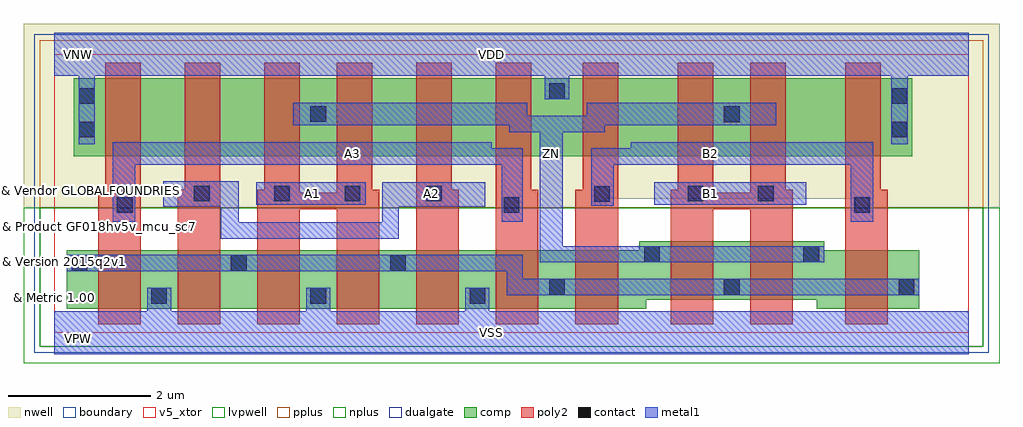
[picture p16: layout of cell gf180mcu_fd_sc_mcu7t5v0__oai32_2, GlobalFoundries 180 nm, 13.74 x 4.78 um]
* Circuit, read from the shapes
.subckt gf180mcu_fd_sc_mcu7t5v0__oai32_2 A1 A2 A3 B1 B2 VDD VNW VSS ZN
XM1 VSS A3 n1 VSUBS nfet_05v0 w=0.82u l=0.6u m=2
XM2 n1 A2 VSS VSUBS nfet_05v0 w=0.82u l=0.6u m=2
XM3 VSS A1 n1 VSUBS nfet_05v0 w=0.82u l=0.6u m=2
XM4 ZN B2 n1 VSUBS nfet_05v0 w=0.82u l=0.6u m=2
XM5 n1 B1 ZN VSUBS nfet_05v0 w=0.82u l=0.6u m=2
XM6 n2 A3 VDD VNW pfet_05v0 w=1.095u l=0.5u
XM7 n3 A2 n2 VNW pfet_05v0 w=1.095u l=0.5u
XM8 ZN A1 n3 VNW pfet_05v0 w=1.095u l=0.5u
XM9 n4 A1 ZN VNW pfet_05v0 w=1.095u l=0.5u
XM10 n5 A2 n4 VNW pfet_05v0 w=1.095u l=0.5u
XM11 VDD A3 n5 VNW pfet_05v0 w=1.095u l=0.5u
XM12 n6 B2 VDD VNW pfet_05v0 w=1.095u l=0.5u
XM13 ZN B1 n6 VNW pfet_05v0 w=1.095u l=0.5u
XM14 n7 B1 ZN VNW pfet_05v0 w=1.095u l=0.5u
XM15 VDD B2 n7 VNW pfet_05v0 w=1.095u l=0.5u
.ends

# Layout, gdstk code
import gdstk
lib = gdstk.Library(unit=1e-6, precision=1e-09)
def R(c, l, rs):  # rectangles x0, y0, x1, y1
    for r in rs: c.add(gdstk.rectangle(r[:2], r[2:], *l))
def A(c, l, x, y, w, h, nx, ny, dx, dy):  # array of equal rectangles
    R(c, l, [(x+i*dx, y+j*dy, x+i*dx+w, y+j*dy+h) for i in range(nx) for j in range(ny)])
def P(c, l, *ps):  # polygons
    for p in ps: c.add(gdstk.Polygon(p, *l))
boundary = (0, 0)
nwell = (21, 0)
comp = (22, 0)
poly2 = (30, 0)
pplus = (31, 0)
nplus = (32, 0)
contact = (33, 0)
metal1 = (34, 0)
dualgate = (55, 0)
v5_xtor = (112, 1)
lvpwell = (204, 0)

gf180mcu_fd_sc_mcu7t5v0_ = lib.new_cell('gf180mcu_fd_sc_mcu7t5v0__oai32_2')
R(gf180mcu_fd_sc_mcu7t5v0_, boundary, [(0,0,12.88,3.92)])
P(gf180mcu_fd_sc_mcu7t5v0_, nwell, [(-0.43,1.76),(-0.43,4.35),(13.31,4.35),(13.31,1.76),(11.28,1.76),(11.28,1.885),(7.77,1.885),(7.77,1.76)])
R(gf180mcu_fd_sc_mcu7t5v0_, comp, [(0.28,2.485,12.08,3.58)])
P(gf180mcu_fd_sc_mcu7t5v0_, comp, [(0.18,0.34),(0.18,1.16),(8.24,1.16),(8.24,1.285),(10.84,1.285),(10.84,1.16),(12.18,1.16),(12.18,0.34),(10.74,0.34),(10.74,0.465),(8.34,0.465),(8.34,0.34)])
P(gf180mcu_fd_sc_mcu7t5v0_, poly2, [(0.62,0.12),(0.62,2.01),(0.72,2.01),(0.72,3.8),(1.22,3.8),(1.22,0.12)],
  [(1.74,0.12),(1.74,2.01),(1.84,2.01),(1.84,3.8),(2.34,3.8),(2.34,0.12)],
  [(2.86,0.12),(2.86,2.01),(2.96,2.01),(2.96,3.8),(3.46,3.8),(3.46,1.97),(3.98,1.97),(3.98,3.8),(4.48,3.8),(4.48,2.01),(4.58,2.01),(4.58,0.12),(3.98,0.12),(3.98,1.74),(3.46,1.74),(3.46,0.12)],
  [(5.1,0.12),(5.1,3.8),(5.6,3.8),(5.6,2.01),(5.7,2.01),(5.7,0.12)],
  [(6.22,0.12),(6.22,3.8),(6.72,3.8),(6.72,2.01),(6.82,2.01),(6.82,0.12)],
  [(7.34,0.12),(7.34,2.01),(7.44,2.01),(7.44,3.8),(7.94,3.8),(7.94,0.12)],
  [(8.68,0.12),(8.68,2.01),(8.78,2.01),(8.78,3.8),(9.28,3.8),(9.28,1.97),(9.8,1.97),(9.8,3.8),(10.3,3.8),(10.3,2.01),(10.4,2.01),(10.4,0.12),(9.8,0.12),(9.8,1.74),(9.28,1.74),(9.28,0.12)],
  [(11.14,0.12),(11.14,3.8),(11.64,3.8),(11.64,2.01),(11.74,2.01),(11.74,0.12)])
R(gf180mcu_fd_sc_mcu7t5v0_, pplus, [(-0.2,1.76,13.08,4.12)])
R(gf180mcu_fd_sc_mcu7t5v0_, nplus, [(-0.2,-0.2,13.08,1.76)])
A(gf180mcu_fd_sc_mcu7t5v0_, contact, 1.37, 0.41, 0.22, 0.22, 3, 1, 2.24, 0)
A(gf180mcu_fd_sc_mcu7t5v0_, contact, 6.97, 0.535, 0.22, 0.22, 3, 1, 2.46, 0)
A(gf180mcu_fd_sc_mcu7t5v0_, contact, 0.25, 0.87, 0.22, 0.22, 3, 1, 2.24, 0)
R(gf180mcu_fd_sc_mcu7t5v0_, contact, [(8.31,0.995,8.53,1.215), (10.55,0.995,10.77,1.215), (0.885,1.69,1.105,1.91), (6.33,1.69,6.55,1.91), (11.265,1.69,11.485,1.91), (7.605,1.845,7.825,2.065), (1.97,1.85,2.19,2.07), (3.1,1.85,3.32,2.07), (4.09,1.85,4.31,2.07), (5.24,1.85,5.46,2.07), (8.92,1.85,9.14,2.07), (9.91,1.85,10.13,2.07), (0.35,2.75,0.57,2.97), (11.79,2.75,12.01,2.97), (9.43,2.965,9.65,3.185), (3.61,2.97,3.83,3.19), (0.35,3.22,0.57,3.44), (11.79,3.22,12.01,3.44), (6.97,3.29,7.19,3.51)])
R(gf180mcu_fd_sc_mcu7t5v0_, metal1, [(2.85,1.8,4.39,2.12), (8.45,1.8,10.59,2.12)])
P(gf180mcu_fd_sc_mcu7t5v0_, metal1, [(2.35,1.325),(2.35,1.77),(1.535,1.77),(1.535,2.135),(2.6,2.135),(2.6,1.555),(4.62,1.555),(4.62,2.12),(6.07,2.12),(6.07,1.77),(4.85,1.77),(4.85,1.325)],
  [(0.825,1.56),(0.825,2.68),(6.16,2.68),(6.16,2.595),(6.6,2.595),(6.6,1.56),(6.3,1.56),(6.3,2.365),(1.145,2.365),(1.145,1.56)],
  [(6.84,0.99),(6.84,2.825),(6.41,2.825),(6.41,2.92),(3.365,2.92),(3.365,3.24),(6.66,3.24),(6.66,3.055),(7.5,3.055),(7.5,3.24),(10.17,3.24),(10.17,2.92),(7.75,2.92),(7.75,2.825),(7.16,2.825),(7.16,1.22),(10.84,1.22),(10.84,0.99)],
  [(11.215,1.56),(11.215,2.365),(7.88,2.365),(7.88,1.785),(7.56,1.785),(7.56,2.595),(8.12,2.595),(8.12,2.68),(11.535,2.68),(11.535,1.56)],
  [(6.37,0.53),(6.37,0.865),(0.18,0.865),(0.18,1.095),(6.6,1.095),(6.6,0.76),(12.18,0.76),(12.18,0.53)],
  [(0,-0.3),(0,0.3),(1.31,0.3),(1.31,0.635),(1.65,0.635),(1.65,0.3),(3.55,0.3),(3.55,0.635),(3.89,0.635),(3.89,0.3),(5.79,0.3),(5.79,0.635),(6.13,0.635),(6.13,0.3),(12.88,0.3),(12.88,-0.3)],
  [(0.345,2.65),(0.345,3.62),(0,3.62),(0,4.22),(12.88,4.22),(12.88,3.62),(12.015,3.62),(12.015,2.65),(11.785,2.65),(11.785,3.62),(7.25,3.62),(7.25,3.285),(6.91,3.285),(6.91,3.62),(0.575,3.62),(0.575,2.65)])
R(gf180mcu_fd_sc_mcu7t5v0_, dualgate, [(-0.28,-0.28,13.16,4.2)])
R(gf180mcu_fd_sc_mcu7t5v0_, v5_xtor, [(0,0,12.88,3.92)])
R(gf180mcu_fd_sc_mcu7t5v0_, lvpwell, [(-0.43,-0.43,13.31,1.76)])
gf180mcu_fd_sc_mcu7t5v0_.add(gdstk.Label('A3', (4.2,2.52), layer=34, texttype=10))
gf180mcu_fd_sc_mcu7t5v0_.add(gdstk.Label('B1', (9.24,1.96), layer=34, texttype=10))
gf180mcu_fd_sc_mcu7t5v0_.add(gdstk.Label('B2', (9.24,2.52), layer=34, texttype=10))
gf180mcu_fd_sc_mcu7t5v0_.add(gdstk.Label('VDD', (6.16,3.92), layer=34, texttype=10))
gf180mcu_fd_sc_mcu7t5v0_.add(gdstk.Label('VSS', (6.16,0), layer=34, texttype=10))
gf180mcu_fd_sc_mcu7t5v0_.add(gdstk.Label('ZN', (7,2.52), layer=34, texttype=10))
gf180mcu_fd_sc_mcu7t5v0_.add(gdstk.Label('A1', (3.64,1.96), layer=34, texttype=10))
gf180mcu_fd_sc_mcu7t5v0_.add(gdstk.Label('A2', (5.32,1.96), layer=34, texttype=10))
gf180mcu_fd_sc_mcu7t5v0_.add(gdstk.Label('& Vendor GLOBALFOUNDRIES', (0,2), layer=63, texttype=63))
gf180mcu_fd_sc_mcu7t5v0_.add(gdstk.Label('& Product GF018hv5v_mcu_sc7', (0,1.5), layer=63, texttype=63))
gf180mcu_fd_sc_mcu7t5v0_.add(gdstk.Label('& Version 2015q2v1', (0,1), layer=63, texttype=63))
gf180mcu_fd_sc_mcu7t5v0_.add(gdstk.Label('& Metric 1.00', (0,0.5), layer=63, texttype=63))
gf180mcu_fd_sc_mcu7t5v0_.add(gdstk.Label('VNW', (0.345,3.92), layer=21, texttype=10))
gf180mcu_fd_sc_mcu7t5v0_.add(gdstk.Label('VPW', (0.34,-0.085), layer=204, texttype=10))

lib.write_gds('gf180mcu_fd_sc_mcu7t5v0__oai32_2.gds')
